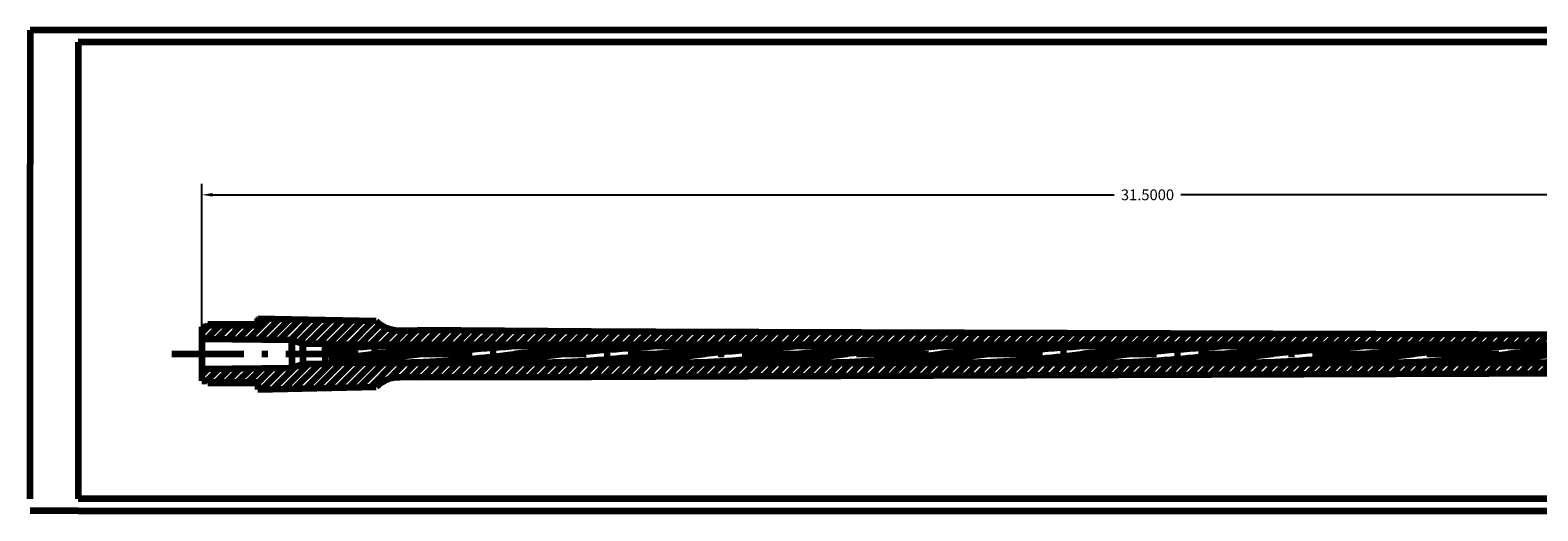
# Model space of a CAD drawing. Units: inches. Extents: x -7.8 to 42.6, y -30.2 to -22.2.
# Drawn here: x -7.8 to 17.3, y -30.2 to -22.2 of the extents above; entities that cross this region are included whole.
import ezdxf

# ---------------------------------------------------------------- set-up
doc = ezdxf.new("R2010")
doc.units = ezdxf.units.IN
doc.header["$LTSCALE"] = 0.1
doc.header["$MEASUREMENT"] = 0
doc.linetypes.add('ACAD_ISO10W100', pattern=[18, 12, -3, 0, -3])
doc.dimstyles.get("Standard").update_dxf_attribs({"dimtxt": 0.18, "dimasz": 0.18, "dimexe": 0.18, "dimexo": 0.0625, "dimgap": 0.09, "dimtad": 0, "dimtih": 1, "dimtoh": 1, "dimdec": 4, "dimzin": 0, "dimdsep": 46, "dimtxsty": 'Standard', "dimcen": 0.09, "dimadec": 0, "dimazin": 0, "dimtfac": 1, "dimtdec": 4, "dimtofl": 0, "dimtmove": 0, "dimatfit": 3, "dimfxl": 0, "dimtolj": 1, "dimtzin": 0, "dimarcsym": 0})
pattern_1 = [(45, (-4.94252, -27.58839), (-0.08838835, 0.08838835), [])]

# ---------------------------------------------------------------- blocks, each defined once
blk = doc.blocks.new('*D2')
at = {"color": 0, "lineweight": -2, "ltscale": 1.4}
for p, q in [((-4.943, -27.526), (-4.943, -24.76)), ((26.557, -27.526), (26.557, -24.76)), ((-4.763, -24.94), (10.252, -24.94)), ((26.377, -24.94), (11.362, -24.94))]:
    blk.add_line(p, q, dxfattribs=at)
at = {"color": 0, "lineweight": 140, "ltscale": 1.4}
for points in [[(-4.763, -24.91), (-4.763, -24.97), (-4.943, -24.94)], [(26.377, -24.91), (26.377, -24.97), (26.557, -24.94)]]:
    blk.add_solid(points, dxfattribs=at)
at = {"layer": 'Defpoints', "color": 0, "lineweight": 140, "ltscale": 1.4}
for p in [(26.557, -24.94), (-4.943, -27.588), (26.557, -27.588)]:
    blk.add_point(p, dxfattribs=at)
at = {"color": 0, "lineweight": 140, "ltscale": 1.4, "insert": (10.807, -24.94), "char_height": 0.18, "attachment_point": 5}
blk.add_mtext('\\A1;31.5000', dxfattribs=at)

msp = doc.modelspace()

# ---------------------------------------------------------------- hatches: boundary and pattern name
at = {"lineweight": 100, "ltscale": 1.4}
h = msp.add_hatch(dxfattribs=at)
h.set_pattern_fill('ANSI31', style=0)
h.set_pattern_definition(pattern_1)
edge = h.paths.add_edge_path()
edge.add_line((-4.94252, -27.13939), (-4.94252, -27.34264))
edge.add_line((-4.94252, -27.34264), (-3.44252, -27.35839))
edge.add_line((-3.44252, -27.35839), (-3.26252, -27.41889))
edge.add_line((-3.26252, -27.41889), (-2.89252, -27.41989))
edge.add_line((-2.89252, -27.41989), (-2.77252, -27.43239))
edge.add_line((-2.77252, -27.43239), (-2.06252, -27.43839))
edge.add_line((-2.06252, -27.43839), (26.55748, -27.43839))
edge.add_line((26.55748, -27.43839), (26.55748, -27.37089))
edge.add_arc((26.48248, -27.37089), 0.075, 0, 90)
edge.add_line((26.48248, -27.29589), (25.49748, -27.29241))
edge.add_line((25.49748, -27.29241), (25.49748, -27.11339))
edge.add_line((25.49748, -27.11339), (25.35248, -27.11339))
edge.add_line((25.35248, -27.11339), (25.37748, -27.19339))
edge.add_line((25.37748, -27.19339), (25.17748, -27.19339))
edge.add_line((25.17748, -27.19339), (25.20248, -27.11339))
edge.add_line((25.20248, -27.11339), (25.06098, -27.11339))
edge.add_line((25.06098, -27.11339), (25.06098, -27.29088))
edge.add_line((25.06098, -27.29088), (22.36748, -27.28139))
edge.add_line((22.36748, -27.28139), (20.28748, -27.27439))
edge.add_line((20.28748, -27.27439), (2.61748, -27.21339))
edge.add_line((2.61748, -27.21339), (1.54748, -27.20939))
edge.add_line((1.54748, -27.20939), (-1.35252, -27.18739))
edge.add_line((-1.35252, -27.18739), (-1.35252, -27.19939))
edge.add_line((-1.35252, -27.19939), (-1.64252, -27.19839))
edge.add_arc((-1.65216, -26.64247), 0.556, 225.404411, 270.99277, ccw=False)
edge.add_line((-2.04252, -27.03839), (-4.01152, -26.99839))
edge.add_line((-4.01152, -26.99839), (-4.01152, -27.09939))
edge.add_line((-4.01152, -27.09939), (-4.8467, -27.09939))
edge.add_line((-4.8467, -27.09939), (-4.86752, -27.13939))
edge.add_line((-4.86752, -27.13939), (-4.94252, -27.13939))
h = msp.add_hatch(dxfattribs=at)
h.set_pattern_fill('ANSI31', style=0)
h.set_pattern_definition(pattern_1)
edge = h.paths.add_edge_path()
edge.add_line((-4.94252, -27.83414), (-4.94252, -28.03739))
edge.add_line((-4.94252, -28.03739), (-4.86752, -28.03739))
edge.add_line((-4.86752, -28.03739), (-4.8467, -28.07739))
edge.add_line((-4.8467, -28.07739), (-4.01152, -28.07739))
edge.add_line((-4.01152, -28.07739), (-4.01152, -28.17839))
edge.add_line((-4.01152, -28.17839), (-2.04252, -28.13839))
edge.add_arc((-1.65216, -28.5343), 0.556, 89.00723, 134.595589, ccw=False)
edge.add_line((-1.64252, -27.97839), (-1.35252, -27.97739))
edge.add_line((-1.35252, -27.97739), (1.54748, -27.96739))
edge.add_line((1.54748, -27.96739), (2.61748, -27.96339))
edge.add_line((2.61748, -27.96339), (20.28748, -27.90239))
edge.add_line((20.28748, -27.90239), (22.36748, -27.89539))
edge.add_line((22.36748, -27.89539), (26.48248, -27.88089))
edge.add_arc((26.48248, -27.80589), 0.075, 270, 360)
edge.add_line((26.55748, -27.80589), (26.55748, -27.73839))
edge.add_line((26.55748, -27.73839), (-2.06252, -27.73839))
edge.add_line((-2.06252, -27.73839), (-2.77252, -27.74439))
edge.add_line((-2.77252, -27.74439), (-2.89252, -27.75689))
edge.add_line((-2.89252, -27.75689), (-3.26252, -27.75789))
edge.add_line((-3.26252, -27.75789), (-3.44252, -27.81839))
edge.add_line((-3.44252, -27.81839), (-4.94252, -27.83414))

# ---------------------------------------------------------------- linework, layer by layer
at = {"color": 7, "lineweight": 140, "ltscale": 1.4}
for p, q in [((42.6, -22.2), (-7.80365, -22.2)), ((42.4, -22.4), (-7.00365, -22.4))]:
    msp.add_line(p, q, dxfattribs=at)
at = {"color": 7, "lineweight": 100, "ltscale": 1.4}
for p, q in [((-7.80365, -22.2), (-7.80365, -24.43536)), ((-7.00365, -22.4), (-7.00365, -30)), ((-7.80365, -30), (-7.80365, -24.43536)), ((-4.8467, -27.09939), (-4.86752, -27.13939)), ((-4.01152, -27.09939), (-4.8467, -27.09939)), ((-4.01152, -26.99839), (-2.04252, -27.03839)), ((-4.01152, -27.09939), (-4.01152, -26.99839)), ((-4.94252, -27.13939), (-4.86752, -27.13939)), ((-4.94252, -27.13939), (-4.94252, -27.34264)), ((-3.44252, -27.35839), (-4.94252, -27.34264)), ((-4.94252, -27.34264), (-4.94252, -27.83414)), ((-3.44252, -27.58839), (-3.44252, -27.35839)), ((-3.44252, -27.35839), (-3.44252, -27.81839)), ((-3.26252, -27.41889), (-3.44252, -27.35839)), ((-1.64252, -27.19839), (-1.35252, -27.19939)), ((-1.35252, -27.19939), (-1.35252, -27.18739)), ((-1.35252, -27.18739), (1.54748, -27.20939)), ((1.54748, -27.20939), (2.61748, -27.21339)), ((2.61748, -27.21339), (20.28748, -27.27439)), ((-3.26252, -27.58839), (-3.26252, -27.41889)), ((-3.26252, -27.41889), (-3.26252, -27.75789)), ((-2.89252, -27.41989), (-3.26252, -27.41889)), ((-2.89252, -27.58839), (-2.89252, -27.41989)), ((-2.89252, -27.41989), (-2.89252, -27.75689)), ((-2.77252, -27.43239), (-2.89252, -27.41989)), ((-2.77252, -27.58839), (-2.77252, -27.43239)), ((-2.77252, -27.43239), (-2.77252, -27.74439)), ((-2.06252, -27.43839), (-2.77252, -27.43239)), ((-2.06252, -27.58839), (-2.06252, -27.43839)), ((-2.06252, -27.43839), (-2.06252, -27.73839)), ((26.55748, -27.43839), (-2.06252, -27.43839)), ((-2.06252, -27.43839), (-2.06252, -27.73839)), ((-4.94252, -27.83414), (-3.44252, -27.81839)), ((-4.94252, -27.83414), (-4.94252, -28.03739)), ((-3.26252, -27.75789), (-3.44252, -27.81839)), ((-2.89252, -27.75689), (-3.26252, -27.75789)), ((-2.77252, -27.74439), (-2.89252, -27.75689)), ((-2.06252, -27.73839), (-2.77252, -27.74439)), ((-2.06252, -27.73839), (26.55748, -27.73839)), ((-4.94252, -28.03739), (-4.86752, -28.03739)), ((-4.8467, -28.07739), (-4.86752, -28.03739)), ((-4.01152, -28.07739), (-4.8467, -28.07739)), ((-4.01152, -28.07739), (-4.01152, -28.17839)), ((-1.35252, -27.97739), (-1.64252, -27.97839)), ((-1.35252, -27.97739), (1.54748, -27.96739)), ((1.54748, -27.96739), (2.61748, -27.96339)), ((2.61748, -27.96339), (20.28748, -27.90239)), ((-4.01152, -28.17839), (-2.04252, -28.13839)), ((35, -30), (-7.00365, -30)), ((-7.00365, -30.2), (-7.80365, -30.2)), ((-7.00365, -30.2), (42.6, -30.2))]:
    msp.add_line(p, q, dxfattribs=at)
at = {"color": 7, "lineweight": 50, "ltscale": 0.7}
for p, q in [((-4.01152, -27.13939), (-4.01152, -27.09939)), ((-4.86752, -27.13939), (-4.01152, -27.13939)), ((-4.94252, -28.03739), (-4.01152, -28.03739)), ((-4.01152, -28.03739), (-4.01152, -28.07739))]:
    msp.add_line(p, q, dxfattribs=at)
at = {"color": 1, "linetype": 'ACAD_ISO10W100', "lineweight": 100}
msp.add_line((-5.44252, -27.58839), (27.05748, -27.58839), dxfattribs=at)
at = {"color": 7, "lineweight": 100, "ltscale": 1.4}
for centre, radius, start, end in [((-1.65216, -26.64247), 0.556, 225.404411, 270.99277), ((-1.1003, -46.11807), 18.67969, 90, 95.136046), ((-1.90628, -46.11807), 18.67969, 90, 92.657961), ((-3.63876, -9.0587), 18.67969, 272.657961, 277.265901), ((-4.44474, -9.0587), 18.67969, 275.136046, 277.265901), ((0.19892, -46.12826), 18.67969, 91.86634, 97.014487), ((0.76554, -46.15615), 18.67969, 93.603773, 96.275318), ((0.45765, -46.11807), 18.67969, 90, 92.657961), ((1.26363, -46.11807), 18.67969, 90, 95.136046), ((-2.08082, -9.0587), 18.67969, 275.136046, 277.265901), ((-1.27484, -9.0587), 18.67969, 272.657961, 277.265901), ((2.56285, -46.12826), 18.67969, 91.86634, 97.014487), ((3.12947, -46.15615), 18.67969, 93.603773, 96.275318), ((3.62613, -46.11807), 18.67969, 90, 95.136046), ((2.82015, -46.11807), 18.67969, 90, 92.657961), ((1.08766, -9.0587), 18.67969, 272.657961, 277.265901), ((0.28168, -9.0587), 18.67969, 275.136046, 277.265901), ((4.92535, -46.12826), 18.67969, 91.86634, 97.014487), ((5.49197, -46.15615), 18.67969, 93.603773, 96.275318), ((5.9872, -46.11807), 18.67969, 90, 95.136046), ((5.18122, -46.11807), 18.67969, 90, 92.657961), ((3.44874, -9.0587), 18.67969, 272.657961, 277.265901), ((2.64276, -9.0587), 18.67969, 275.136046, 277.265901), ((7.28642, -46.12826), 18.67969, 91.86634, 97.014487), ((7.85304, -46.15615), 18.67969, 93.603773, 96.275318), ((7.54372, -46.11807), 18.67969, 90, 92.657961), ((8.3497, -46.11807), 18.67969, 90, 95.136046), ((5.00526, -9.0587), 18.67969, 275.136046, 277.265901), ((5.81124, -9.0587), 18.67969, 272.657961, 277.265901), ((9.64892, -46.12826), 18.67969, 91.86634, 97.014487), ((10.21554, -46.15615), 18.67969, 93.603773, 96.275318), ((10.7122, -46.11807), 18.67969, 90, 95.136046), ((9.90622, -46.11807), 18.67969, 90, 92.657961), ((8.17374, -9.0587), 18.67969, 272.657961, 277.265901), ((7.36776, -9.0587), 18.67969, 275.136046, 277.265901), ((12.01142, -46.12826), 18.67969, 91.86634, 97.014487), ((12.57804, -46.15615), 18.67969, 93.603773, 96.275318), ((12.26872, -46.11807), 18.67969, 90, 92.657961), ((13.0747, -46.11807), 18.67969, 90, 95.136046), ((10.53624, -9.0587), 18.67969, 272.657961, 277.265901), ((9.73026, -9.0587), 18.67969, 275.136046, 277.265901), ((14.37392, -46.12826), 18.67969, 91.86634, 97.014487), ((14.94054, -46.15615), 18.67969, 93.603773, 96.275318), ((15.4372, -46.11807), 18.67969, 90, 95.136046), ((14.63122, -46.11807), 18.67969, 90, 92.657961), ((12.89874, -9.0587), 18.67969, 272.657961, 277.265901), ((12.09276, -9.0587), 18.67969, 275.136046, 277.265901), ((16.73642, -46.12826), 18.67969, 91.86634, 97.014487), ((17.30304, -46.15615), 18.67969, 93.603773, 96.275318), ((17.7997, -46.11807), 18.67969, 90, 95.136046), ((16.99372, -46.11807), 18.67969, 90, 92.657961), ((15.26124, -9.0587), 18.67969, 272.657961, 277.265901), ((14.45526, -9.0587), 18.67969, 275.136046, 277.265901), ((19.09892, -46.12826), 18.67969, 91.86634, 97.014487), ((-2.08224, -9.0587), 18.67969, 270, 275.136046), ((-1.27626, -9.0587), 18.67969, 270, 272.657961), ((0.28168, -9.0587), 18.67969, 270, 275.136046), ((1.08766, -9.0587), 18.67969, 270, 272.657961), ((2.64418, -9.0587), 18.67969, 270, 275.136046), ((3.45016, -9.0587), 18.67969, 270, 272.657961), ((5.00526, -9.0587), 18.67969, 270, 275.136046), ((5.81124, -9.0587), 18.67969, 270, 272.657961), ((7.36776, -9.0587), 18.67969, 270, 275.136046), ((8.17374, -9.0587), 18.67969, 270, 272.657961), ((9.73026, -9.0587), 18.67969, 270, 275.136046), ((10.53624, -9.0587), 18.67969, 270, 272.657961), ((12.09276, -9.0587), 18.67969, 270, 275.136046), ((12.89874, -9.0587), 18.67969, 270, 272.657961), ((14.45526, -9.0587), 18.67969, 270, 275.136046), ((15.26124, -9.0587), 18.67969, 270, 272.657961), ((16.81776, -9.0587), 18.67969, 270, 275.136046), ((-1.65216, -28.5343), 0.556, 89.00723, 134.595589)]:
    msp.add_arc(centre, radius, start, end, dxfattribs=at)

# ---------------------------------------------------------------- dimensions: what is measured, and where the dimension line sits
at = {"color": 3, "lineweight": 140, "ltscale": 1.4}
dim = msp.add_linear_dim(base=(26.55748, -24.93999), p1=(-4.94252, -27.58839), p2=(26.55748, -27.58839), dimstyle='Standard', dxfattribs=at)
dim.commit()
dim.dimension.update_dxf_attribs({"geometry": '*D2', "text_midpoint": (10.80748, -24.93999)})

doc.saveas('drawing.dxf')
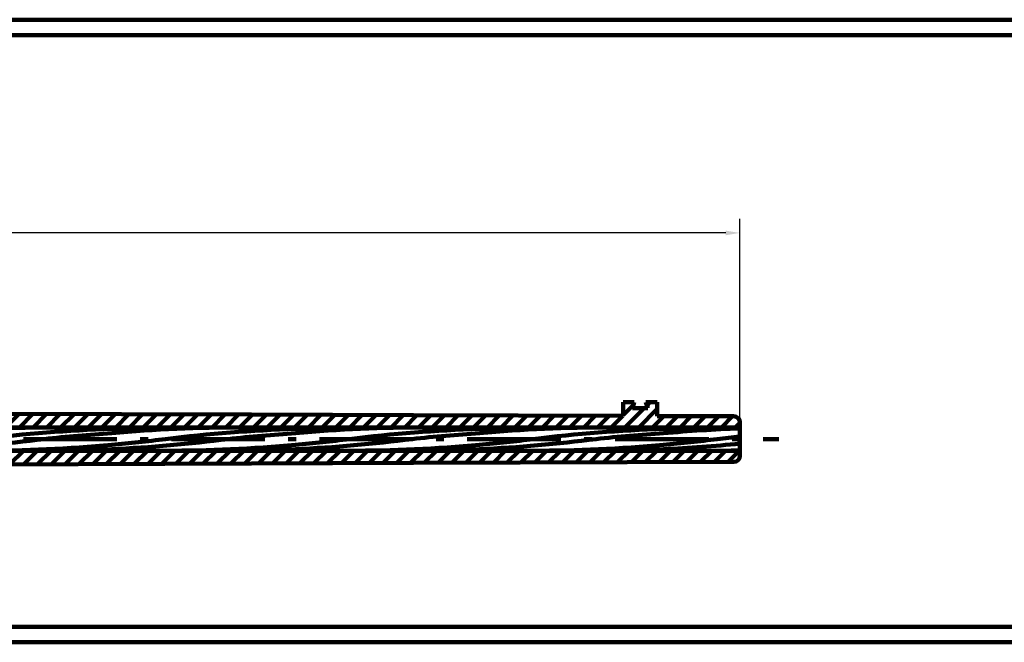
# Model space of a CAD drawing. Units: inches. Extents: x -7.8 to 42.6, y -30.2 to -22.2.
# Drawn here: x 17.3 to 30, y -30.2 to -22.2 of the extents above; entities that cross this region are included whole.
import ezdxf

# ---------------------------------------------------------------- set-up
doc = ezdxf.new("R2010")
doc.units = ezdxf.units.IN
doc.header["$LTSCALE"] = 0.1
doc.header["$MEASUREMENT"] = 0
doc.linetypes.add('ACAD_ISO10W100', pattern=[18, 12, -3, 0, -3])
doc.dimstyles.get("Standard").update_dxf_attribs({"dimtxt": 0.18, "dimasz": 0.18, "dimexe": 0.18, "dimexo": 0.0625, "dimgap": 0.09, "dimtad": 0, "dimtih": 1, "dimtoh": 1, "dimdec": 4, "dimzin": 0, "dimdsep": 46, "dimtxsty": 'Standard', "dimcen": 0.09, "dimadec": 0, "dimazin": 0, "dimtfac": 1, "dimtdec": 4, "dimtofl": 0, "dimtmove": 0, "dimatfit": 3, "dimfxl": 0, "dimtolj": 1, "dimtzin": 0, "dimarcsym": 0})
pattern_1 = [(45, (-4.94252, -27.58839), (-0.08838835, 0.08838835), [])]

# ---------------------------------------------------------------- blocks, each defined once
blk = doc.blocks.new('*D2')
at = {"color": 0, "lineweight": -2, "ltscale": 1.4}
for p, q in [((-4.943, -27.526), (-4.943, -24.76)), ((26.557, -27.526), (26.557, -24.76)), ((-4.763, -24.94), (10.252, -24.94)), ((26.377, -24.94), (11.362, -24.94))]:
    blk.add_line(p, q, dxfattribs=at)
at = {"color": 0, "lineweight": 140, "ltscale": 1.4}
for points in [[(-4.763, -24.91), (-4.763, -24.97), (-4.943, -24.94)], [(26.377, -24.91), (26.377, -24.97), (26.557, -24.94)]]:
    blk.add_solid(points, dxfattribs=at)
at = {"layer": 'Defpoints', "color": 0, "lineweight": 140, "ltscale": 1.4}
for p in [(26.557, -24.94), (-4.943, -27.588), (26.557, -27.588)]:
    blk.add_point(p, dxfattribs=at)
at = {"color": 0, "lineweight": 140, "ltscale": 1.4, "insert": (10.807, -24.94), "char_height": 0.18, "attachment_point": 5}
blk.add_mtext('\\A1;31.5000', dxfattribs=at)

msp = doc.modelspace()

# ---------------------------------------------------------------- hatches: boundary and pattern name
at = {"lineweight": 100, "ltscale": 1.4}
h = msp.add_hatch(dxfattribs=at)
h.set_pattern_fill('ANSI31', style=0)
h.set_pattern_definition(pattern_1)
edge = h.paths.add_edge_path()
edge.add_line((-4.94252, -27.13939), (-4.94252, -27.34264))
edge.add_line((-4.94252, -27.34264), (-3.44252, -27.35839))
edge.add_line((-3.44252, -27.35839), (-3.26252, -27.41889))
edge.add_line((-3.26252, -27.41889), (-2.89252, -27.41989))
edge.add_line((-2.89252, -27.41989), (-2.77252, -27.43239))
edge.add_line((-2.77252, -27.43239), (-2.06252, -27.43839))
edge.add_line((-2.06252, -27.43839), (26.55748, -27.43839))
edge.add_line((26.55748, -27.43839), (26.55748, -27.37089))
edge.add_arc((26.48248, -27.37089), 0.075, 0, 90)
edge.add_line((26.48248, -27.29589), (25.49748, -27.29241))
edge.add_line((25.49748, -27.29241), (25.49748, -27.11339))
edge.add_line((25.49748, -27.11339), (25.35248, -27.11339))
edge.add_line((25.35248, -27.11339), (25.37748, -27.19339))
edge.add_line((25.37748, -27.19339), (25.17748, -27.19339))
edge.add_line((25.17748, -27.19339), (25.20248, -27.11339))
edge.add_line((25.20248, -27.11339), (25.06098, -27.11339))
edge.add_line((25.06098, -27.11339), (25.06098, -27.29088))
edge.add_line((25.06098, -27.29088), (22.36748, -27.28139))
edge.add_line((22.36748, -27.28139), (20.28748, -27.27439))
edge.add_line((20.28748, -27.27439), (2.61748, -27.21339))
edge.add_line((2.61748, -27.21339), (1.54748, -27.20939))
edge.add_line((1.54748, -27.20939), (-1.35252, -27.18739))
edge.add_line((-1.35252, -27.18739), (-1.35252, -27.19939))
edge.add_line((-1.35252, -27.19939), (-1.64252, -27.19839))
edge.add_arc((-1.65216, -26.64247), 0.556, 225.404411, 270.99277, ccw=False)
edge.add_line((-2.04252, -27.03839), (-4.01152, -26.99839))
edge.add_line((-4.01152, -26.99839), (-4.01152, -27.09939))
edge.add_line((-4.01152, -27.09939), (-4.8467, -27.09939))
edge.add_line((-4.8467, -27.09939), (-4.86752, -27.13939))
edge.add_line((-4.86752, -27.13939), (-4.94252, -27.13939))
h = msp.add_hatch(dxfattribs=at)
h.set_pattern_fill('ANSI31', style=0)
h.set_pattern_definition(pattern_1)
edge = h.paths.add_edge_path()
edge.add_line((-4.94252, -27.83414), (-4.94252, -28.03739))
edge.add_line((-4.94252, -28.03739), (-4.86752, -28.03739))
edge.add_line((-4.86752, -28.03739), (-4.8467, -28.07739))
edge.add_line((-4.8467, -28.07739), (-4.01152, -28.07739))
edge.add_line((-4.01152, -28.07739), (-4.01152, -28.17839))
edge.add_line((-4.01152, -28.17839), (-2.04252, -28.13839))
edge.add_arc((-1.65216, -28.5343), 0.556, 89.00723, 134.595589, ccw=False)
edge.add_line((-1.64252, -27.97839), (-1.35252, -27.97739))
edge.add_line((-1.35252, -27.97739), (1.54748, -27.96739))
edge.add_line((1.54748, -27.96739), (2.61748, -27.96339))
edge.add_line((2.61748, -27.96339), (20.28748, -27.90239))
edge.add_line((20.28748, -27.90239), (22.36748, -27.89539))
edge.add_line((22.36748, -27.89539), (26.48248, -27.88089))
edge.add_arc((26.48248, -27.80589), 0.075, 270, 360)
edge.add_line((26.55748, -27.80589), (26.55748, -27.73839))
edge.add_line((26.55748, -27.73839), (-2.06252, -27.73839))
edge.add_line((-2.06252, -27.73839), (-2.77252, -27.74439))
edge.add_line((-2.77252, -27.74439), (-2.89252, -27.75689))
edge.add_line((-2.89252, -27.75689), (-3.26252, -27.75789))
edge.add_line((-3.26252, -27.75789), (-3.44252, -27.81839))
edge.add_line((-3.44252, -27.81839), (-4.94252, -27.83414))

# ---------------------------------------------------------------- linework, layer by layer
at = {"color": 7, "lineweight": 140, "ltscale": 1.4}
for p, q in [((42.6, -22.2), (-7.80365, -22.2)), ((42.4, -22.4), (-7.00365, -22.4))]:
    msp.add_line(p, q, dxfattribs=at)
at = {"color": 7, "lineweight": 100, "ltscale": 1.4}
for p, q in [((25.20248, -27.11339), (25.06098, -27.11339)), ((25.06098, -27.29088), (25.06098, -27.11339)), ((25.20248, -27.11339), (25.17748, -27.19339)), ((25.35248, -27.11339), (25.37748, -27.19339)), ((25.37748, -27.19339), (25.35248, -27.11339)), ((25.35248, -27.11339), (25.49748, -27.11339)), ((25.49748, -27.11339), (25.49748, -27.29241)), ((25.49748, -27.29241), (25.49748, -27.11339)), ((2.61748, -27.21339), (20.28748, -27.27439)), ((20.28748, -27.27439), (22.36748, -27.28139)), ((25.06098, -27.29088), (22.36748, -27.28139)), ((25.17748, -27.19339), (25.37748, -27.19339)), ((25.49748, -27.29241), (26.48248, -27.29589)), ((25.49748, -27.29241), (26.48248, -27.29589)), ((26.55748, -27.43839), (-2.06252, -27.43839)), ((26.55748, -27.43839), (26.55748, -27.37089)), ((26.55748, -27.58839), (26.55748, -27.43839)), ((26.55748, -27.73839), (26.55748, -27.58839)), ((-2.06252, -27.73839), (26.55748, -27.73839)), ((26.55748, -27.80589), (26.55748, -27.73839)), ((2.61748, -27.96339), (20.28748, -27.90239)), ((20.28748, -27.90239), (22.36748, -27.89539)), ((22.36748, -27.89539), (26.48248, -27.88089)), ((35, -30), (-7.00365, -30)), ((-7.00365, -30.2), (42.6, -30.2))]:
    msp.add_line(p, q, dxfattribs=at)
at = {"color": 1, "linetype": 'ACAD_ISO10W100', "lineweight": 100}
msp.add_line((-5.44252, -27.58839), (27.05748, -27.58839), dxfattribs=at)
at = {"color": 7, "lineweight": 100, "ltscale": 1.4}
for centre, radius, start, end in [((26.48248, -27.37089), 0.075, 0, 90), ((17.7997, -46.11807), 18.67969, 90, 95.136046), ((19.35622, -46.11807), 18.67969, 90, 92.657961), ((20.1622, -46.11807), 18.67969, 90, 95.136046), ((22.5247, -46.11807), 18.67969, 90, 95.136046), ((21.71872, -46.11807), 18.67969, 90, 92.657961), ((24.8872, -46.11807), 18.67969, 90, 95.136046), ((24.08122, -46.11807), 18.67969, 90, 92.657961), ((26.44372, -46.11807), 18.67969, 90, 92.657961), ((19.09892, -46.12826), 18.67969, 91.86634, 97.014487), ((19.66554, -46.15615), 18.67969, 93.603773, 96.275318), ((21.46142, -46.12826), 18.67969, 91.86634, 97.014487), ((22.02804, -46.15615), 18.67969, 93.603773, 96.275318), ((23.82392, -46.12826), 18.67969, 91.86634, 97.014487), ((24.39054, -46.15615), 18.67969, 93.603773, 96.275318), ((26.18642, -46.12826), 18.67969, 91.86634, 97.014487), ((26.75304, -46.15615), 18.67969, 93.603773, 96.275318), ((27.2497, -46.11807), 18.67969, 92.123725, 95.136046), ((28.54892, -46.12826), 18.67969, 96.119949, 97.014487), ((15.26124, -9.0587), 18.67969, 272.657961, 277.265901), ((16.81776, -9.0587), 18.67969, 270, 275.136046), ((16.81776, -9.0587), 18.67969, 275.136046, 277.265901), ((17.62374, -9.0587), 18.67969, 272.657961, 277.265901), ((19.18026, -9.0587), 18.67969, 270, 275.136046), ((19.98624, -9.0587), 18.67969, 272.657961, 277.265901), ((19.18026, -9.0587), 18.67969, 275.136046, 277.265901), ((21.54276, -9.0587), 18.67969, 270, 275.136046), ((22.34874, -9.0587), 18.67969, 272.657961, 277.265901), ((21.54276, -9.0587), 18.67969, 275.136046, 277.265901), ((23.90526, -9.0587), 18.67969, 270, 275.136046), ((23.90526, -9.0587), 18.67969, 275.136046, 277.265901), ((24.71124, -9.0587), 18.67969, 272.657961, 275.6722), ((17.62374, -9.0587), 18.67969, 270, 272.657961), ((19.98624, -9.0587), 18.67969, 270, 272.657961), ((22.34874, -9.0587), 18.67969, 270, 272.657961), ((24.71124, -9.0587), 18.67969, 270, 272.657961), ((26.26776, -9.0587), 18.67969, 270, 270.888695), ((26.48248, -27.80589), 0.075, 270, 0)]:
    msp.add_arc(centre, radius, start, end, dxfattribs=at)

# ---------------------------------------------------------------- dimensions: what is measured, and where the dimension line sits
at = {"color": 3, "lineweight": 140, "ltscale": 1.4}
dim = msp.add_linear_dim(base=(26.55748, -24.93999), p1=(-4.94252, -27.58839), p2=(26.55748, -27.58839), dimstyle='Standard', dxfattribs=at)
dim.commit()
dim.dimension.update_dxf_attribs({"geometry": '*D2', "text_midpoint": (10.80748, -24.93999)})

doc.saveas('drawing.dxf')
